VERSION 5.7 ;
  NOWIREEXTENSIONATPIN ON ;
  DIVIDERCHAR "/" ;
  BUSBITCHARS "[]" ;
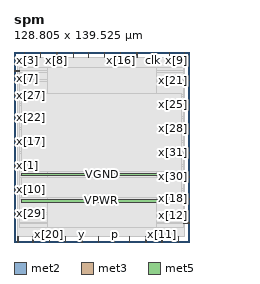
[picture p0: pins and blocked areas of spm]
MACRO spm
  CLASS BLOCK ;
  FOREIGN spm ;
  ORIGIN 0.000 0.000 ;
  SIZE 128.805 BY 139.525 ;
  PIN clk
    DIRECTION INPUT ;
    PORT
      LAYER met2 ;
        RECT 102.210 135.525 102.490 139.525 ;
    END
  END clk
  PIN p
    DIRECTION OUTPUT TRISTATE ;
    PORT
      LAYER met2 ;
        RECT 73.690 0.000 73.970 4.000 ;
    END
  END p
  PIN rst
    DIRECTION INPUT ;
    PORT
      LAYER met2 ;
        RECT 13.890 0.000 14.170 4.000 ;
    END
  END rst
  PIN x[0]
    DIRECTION INPUT ;
    PORT
      LAYER met2 ;
        RECT 2.850 0.000 3.130 4.000 ;
    END
  END x[0]
  PIN x[10]
    DIRECTION INPUT ;
    PORT
      LAYER met3 ;
        RECT 0.000 38.120 4.000 38.720 ;
    END
  END x[10]
  PIN x[11]
    DIRECTION INPUT ;
    PORT
      LAYER met2 ;
        RECT 108.650 0.000 108.930 4.000 ;
    END
  END x[11]
  PIN x[12]
    DIRECTION INPUT ;
    PORT
      LAYER met3 ;
        RECT 124.805 13.640 128.805 14.240 ;
    END
  END x[12]
  PIN x[13]
    DIRECTION INPUT ;
    PORT
      LAYER met2 ;
        RECT 37.810 0.000 38.090 4.000 ;
    END
  END x[13]
  PIN x[14]
    DIRECTION INPUT ;
    PORT
      LAYER met2 ;
        RECT 54.370 135.525 54.650 139.525 ;
    END
  END x[14]
  PIN x[15]
    DIRECTION INPUT ;
    PORT
      LAYER met2 ;
        RECT 19.410 135.525 19.690 139.525 ;
    END
  END x[15]
  PIN x[16]
    DIRECTION INPUT ;
    PORT
      LAYER met2 ;
        RECT 78.290 135.525 78.570 139.525 ;
    END
  END x[16]
  PIN x[17]
    DIRECTION INPUT ;
    PORT
      LAYER met3 ;
        RECT 0.000 73.480 4.000 74.080 ;
    END
  END x[17]
  PIN x[18]
    DIRECTION INPUT ;
    PORT
      LAYER met3 ;
        RECT 124.805 31.320 128.805 31.920 ;
    END
  END x[18]
  PIN x[19]
    DIRECTION INPUT ;
    PORT
      LAYER met2 ;
        RECT 120.610 0.000 120.890 4.000 ;
    END
  END x[19]
  PIN x[1]
    DIRECTION INPUT ;
    PORT
      LAYER met3 ;
        RECT 0.000 55.800 4.000 56.400 ;
    END
  END x[1]
  PIN x[20]
    DIRECTION INPUT ;
    PORT
      LAYER met2 ;
        RECT 25.850 0.000 26.130 4.000 ;
    END
  END x[20]
  PIN x[21]
    DIRECTION INPUT ;
    PORT
      LAYER met3 ;
        RECT 124.805 118.360 128.805 118.960 ;
    END
  END x[21]
  PIN x[22]
    DIRECTION INPUT ;
    PORT
      LAYER met3 ;
        RECT 0.000 91.160 4.000 91.760 ;
    END
  END x[22]
  PIN x[23]
    DIRECTION INPUT ;
    PORT
      LAYER met2 ;
        RECT 114.170 135.525 114.450 139.525 ;
    END
  END x[23]
  PIN x[24]
    DIRECTION INPUT ;
    PORT
      LAYER met2 ;
        RECT 43.330 135.525 43.610 139.525 ;
    END
  END x[24]
  PIN x[25]
    DIRECTION INPUT ;
    PORT
      LAYER met3 ;
        RECT 124.805 100.680 128.805 101.280 ;
    END
  END x[25]
  PIN x[26]
    DIRECTION INPUT ;
    PORT
      LAYER met2 ;
        RECT 96.690 0.000 96.970 4.000 ;
    END
  END x[26]
  PIN x[27]
    DIRECTION INPUT ;
    PORT
      LAYER met3 ;
        RECT 0.000 107.480 4.000 108.080 ;
    END
  END x[27]
  PIN x[28]
    DIRECTION INPUT ;
    PORT
      LAYER met3 ;
        RECT 124.805 83.000 128.805 83.600 ;
    END
  END x[28]
  PIN x[29]
    DIRECTION INPUT ;
    PORT
      LAYER met3 ;
        RECT 0.000 20.440 4.000 21.040 ;
    END
  END x[29]
  PIN x[2]
    DIRECTION INPUT ;
    PORT
      LAYER met2 ;
        RECT 61.730 0.000 62.010 4.000 ;
    END
  END x[2]
  PIN x[30]
    DIRECTION INPUT ;
    PORT
      LAYER met3 ;
        RECT 124.805 47.640 128.805 48.240 ;
    END
  END x[30]
  PIN x[31]
    DIRECTION INPUT ;
    PORT
      LAYER met3 ;
        RECT 124.805 65.320 128.805 65.920 ;
    END
  END x[31]
  PIN x[3]
    DIRECTION INPUT ;
    PORT
      LAYER met2 ;
        RECT 7.450 135.525 7.730 139.525 ;
    END
  END x[3]
  PIN x[4]
    DIRECTION INPUT ;
    PORT
      LAYER met2 ;
        RECT 90.250 135.525 90.530 139.525 ;
    END
  END x[4]
  PIN x[5]
    DIRECTION INPUT ;
    PORT
      LAYER met2 ;
        RECT 84.730 0.000 85.010 4.000 ;
    END
  END x[5]
  PIN x[6]
    DIRECTION INPUT ;
    PORT
      LAYER met2 ;
        RECT 66.330 135.525 66.610 139.525 ;
    END
  END x[6]
  PIN x[7]
    DIRECTION INPUT ;
    PORT
      LAYER met3 ;
        RECT 0.000 125.160 4.000 125.760 ;
    END
  END x[7]
  PIN x[8]
    DIRECTION INPUT ;
    PORT
      LAYER met2 ;
        RECT 31.370 135.525 31.650 139.525 ;
    END
  END x[8]
  PIN x[9]
    DIRECTION INPUT ;
    PORT
      LAYER met2 ;
        RECT 125.210 135.525 125.490 139.525 ;
    END
  END x[9]
  PIN y
    DIRECTION INPUT ;
    PORT
      LAYER met2 ;
        RECT 49.770 0.000 50.050 4.000 ;
    END
  END y
  PIN VPWR
    DIRECTION INPUT ;
    USE POWER ;
    PORT
      LAYER met5 ;
        RECT 5.520 29.335 123.280 30.935 ;
    END
  END VPWR
  PIN VGND
    DIRECTION INPUT ;
    USE GROUND ;
    PORT
      LAYER met5 ;
        RECT 5.520 48.825 123.280 50.425 ;
    END
  END VGND
  OBS
      LAYER li1 ;
        RECT 12.565 11.985 118.075 126.735 ;
      LAYER met1 ;
        RECT 2.830 10.640 125.510 128.080 ;
      LAYER met2 ;
        RECT 2.860 135.245 7.170 135.525 ;
        RECT 8.010 135.245 19.130 135.525 ;
        RECT 19.970 135.245 31.090 135.525 ;
        RECT 31.930 135.245 43.050 135.525 ;
        RECT 43.890 135.245 54.090 135.525 ;
        RECT 54.930 135.245 66.050 135.525 ;
        RECT 66.890 135.245 78.010 135.525 ;
        RECT 78.850 135.245 89.970 135.525 ;
        RECT 90.810 135.245 101.930 135.525 ;
        RECT 102.770 135.245 113.890 135.525 ;
        RECT 114.730 135.245 124.930 135.525 ;
        RECT 2.860 4.280 125.480 135.245 ;
        RECT 3.410 4.000 13.610 4.280 ;
        RECT 14.450 4.000 25.570 4.280 ;
        RECT 26.410 4.000 37.530 4.280 ;
        RECT 38.370 4.000 49.490 4.280 ;
        RECT 50.330 4.000 61.450 4.280 ;
        RECT 62.290 4.000 73.410 4.280 ;
        RECT 74.250 4.000 84.450 4.280 ;
        RECT 85.290 4.000 96.410 4.280 ;
        RECT 97.250 4.000 108.370 4.280 ;
        RECT 109.210 4.000 120.330 4.280 ;
        RECT 121.170 4.000 125.480 4.280 ;
      LAYER met3 ;
        RECT 4.000 126.160 124.805 128.005 ;
        RECT 4.400 124.760 124.805 126.160 ;
        RECT 4.000 119.360 124.805 124.760 ;
        RECT 4.000 117.960 124.405 119.360 ;
        RECT 4.000 108.480 124.805 117.960 ;
        RECT 4.400 107.080 124.805 108.480 ;
        RECT 4.000 101.680 124.805 107.080 ;
        RECT 4.000 100.280 124.405 101.680 ;
        RECT 4.000 92.160 124.805 100.280 ;
        RECT 4.400 90.760 124.805 92.160 ;
        RECT 4.000 84.000 124.805 90.760 ;
        RECT 4.000 82.600 124.405 84.000 ;
        RECT 4.000 74.480 124.805 82.600 ;
        RECT 4.400 73.080 124.805 74.480 ;
        RECT 4.000 66.320 124.805 73.080 ;
        RECT 4.000 64.920 124.405 66.320 ;
        RECT 4.000 56.800 124.805 64.920 ;
        RECT 4.400 55.400 124.805 56.800 ;
        RECT 4.000 48.640 124.805 55.400 ;
        RECT 4.000 47.240 124.405 48.640 ;
        RECT 4.000 39.120 124.805 47.240 ;
        RECT 4.400 37.720 124.805 39.120 ;
        RECT 4.000 32.320 124.805 37.720 ;
        RECT 4.000 30.920 124.405 32.320 ;
        RECT 4.000 21.440 124.805 30.920 ;
        RECT 4.400 20.040 124.805 21.440 ;
        RECT 4.000 14.640 124.805 20.040 ;
        RECT 4.000 13.240 124.405 14.640 ;
        RECT 4.000 10.715 124.805 13.240 ;
      LAYER met4 ;
        RECT 24.345 10.640 104.450 128.080 ;
      LAYER met5 ;
        RECT 5.520 52.025 123.280 108.905 ;
        RECT 5.520 32.535 123.280 47.225 ;
  END
END spm
END LIBRARY

